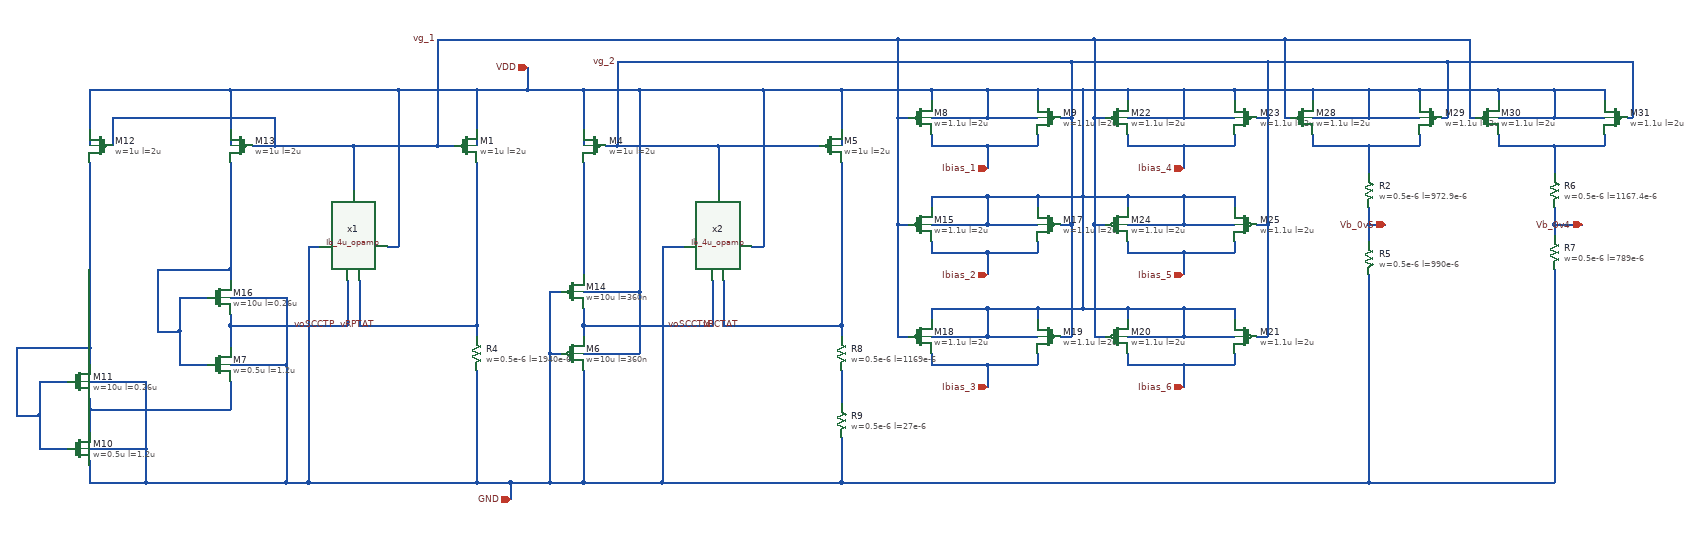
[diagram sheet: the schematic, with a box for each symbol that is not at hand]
v {xschem version=3.4.6 file_version=1.2}
G {}
K {}
V {}
S {}
E {}
N 1170 -670 1170 -650 {lab=voSCCTN}
N 1410 -990 1410 -910 {lab=vg_2}
N 1170 -1090 1170 -990 {lab=VDD}
N 1630 -1090 1630 -990 {lab=VDD}
N 290 -1090 540 -1090 {lab=VDD}
N 980 -1090 980 -990 {lab=VDD}
N 910 -990 940 -990 {lab=vg_1}
N 760 -990 910 -990 {lab=vg_1}
N 540 -1090 540 -990 {lab=VDD}
N 760 -990 760 -910 {lab=vg_1}
N 620 -990 760 -990 {lab=vg_1}
N 820 -810 840 -810 {lab=VDD}
N 840 -1090 840 -810 {lab=VDD}
N 540 -1090 840 -1090 {lab=VDD}
N 540 -670 540 -630 {lab=voSCCTP}
N 540 -720 640 -720 {lab=GND}
N 640 -720 640 -600 {lab=GND}
N 540 -600 640 -600 {lab=GND}
N 450 -720 500 -720 {lab=#net1}
N 450 -660 450 -600 {lab=#net1}
N 450 -600 500 -600 {lab=#net1}
N 540 -770 540 -750 {lab=#net1}
N 410 -660 450 -660 {lab=#net1}
N 450 -720 450 -660 {lab=#net1}
N 410 -770 410 -660 {lab=#net1}
N 410 -770 540 -770 {lab=#net1}
N 540 -960 540 -770 {lab=#net1}
N 540 -670 750 -670 {lab=voSCCTP}
N 540 -690 540 -670 {lab=voSCCTP}
N 750 -750 750 -670 {lab=voSCCTP}
N 290 -520 290 -480 {lab=#net2}
N 290 -570 390 -570 {lab=GND}
N 390 -570 390 -450 {lab=GND}
N 290 -450 390 -450 {lab=GND}
N 200 -570 250 -570 {lab=#net3}
N 200 -510 200 -450 {lab=#net3}
N 200 -450 250 -450 {lab=#net3}
N 160 -510 200 -510 {lab=#net3}
N 200 -570 200 -510 {lab=#net3}
N 290 -520 540 -520 {lab=#net2}
N 290 -540 290 -520 {lab=#net2}
N 540 -570 540 -520 {lab=#net2}
N 290 -630 290 -600 {lab=#net3}
N 290 -1090 290 -990 {lab=VDD}
N 330 -1040 330 -990 {lab=vg_1}
N 330 -1040 620 -1040 {lab=vg_1}
N 620 -1040 620 -990 {lab=vg_1}
N 580 -990 620 -990 {lab=vg_1}
N 290 -430 290 -390 {lab=GND}
N 160 -630 160 -510 {lab=#net3}
N 160 -630 290 -630 {lab=#net3}
N 290 -960 290 -630 {lab=#net3}
N 640 -600 640 -390 {lab=GND}
N 390 -390 640 -390 {lab=GND}
N 390 -450 390 -390 {lab=GND}
N 290 -390 390 -390 {lab=GND}
N 1170 -620 1270 -620 {lab=VDD}
N 1490 -1090 1630 -1090 {lab=VDD}
N 980 -670 980 -650 {lab=vRPTAT}
N 980 -590 980 -390 {lab=GND}
N 770 -750 770 -670 {lab=vRPTAT}
N 770 -670 980 -670 {lab=vRPTAT}
N 980 -960 980 -670 {lab=vRPTAT}
N 1630 -670 1630 -650 {lab=vRCTAT}
N 1420 -670 1630 -670 {lab=vRCTAT}
N 1630 -960 1630 -670 {lab=vRCTAT}
N 1420 -750 1420 -670 {lab=vRCTAT}
N 1400 -750 1400 -670 {lab=voSCCTN}
N 1170 -960 1170 -760 {lab=#net4}
N 1170 -590 1170 -390 {lab=GND}
N 1170 -670 1400 -670 {lab=voSCCTN}
N 1170 -700 1170 -670 {lab=voSCCTN}
N 1270 -730 1270 -620 {lab=VDD}
N 1170 -1090 1270 -1090 {lab=VDD}
N 1310 -810 1350 -810 {lab=GND}
N 1310 -810 1310 -390 {lab=GND}
N 1470 -810 1490 -810 {lab=VDD}
N 1490 -1090 1490 -810 {lab=VDD}
N 1270 -1090 1490 -1090 {lab=VDD}
N 680 -810 700 -810 {lab=GND}
N 680 -810 680 -390 {lab=GND}
N 1170 -730 1270 -730 {lab=VDD}
N 1270 -1090 1270 -730 {lab=VDD}
N 1410 -990 1590 -990 {lab=vg_2}
N 2570 -850 2600 -850 {lab=Vb_0v5}
N 2900 -850 2950 -850 {lab=Vb_0v4}
N 1630 -590 1630 -530 {lab=#net5}
N 1630 -470 1630 -390 {lab=GND}
N 640 -390 680 -390 {lab=GND}
N 1310 -390 1630 -390 {lab=GND}
N 1790 -1090 1790 -1070 {lab=VDD}
N 1890 -1090 1980 -1090 {lab=VDD}
N 1980 -1090 1980 -1070 {lab=VDD}
N 1890 -1040 1980 -1040 {lab=VDD}
N 1890 -1090 1890 -1040 {lab=VDD}
N 1790 -1090 1890 -1090 {lab=VDD}
N 1790 -1040 1890 -1040 {lab=VDD}
N 1790 -1010 1790 -990 {lab=Ibias_1}
N 1890 -990 1980 -990 {lab=Ibias_1}
N 1980 -1010 1980 -990 {lab=Ibias_1}
N 1790 -900 1790 -880 {lab=VDD}
N 1890 -900 1980 -900 {lab=VDD}
N 1980 -900 1980 -880 {lab=VDD}
N 1890 -850 1980 -850 {lab=VDD}
N 1890 -900 1890 -850 {lab=VDD}
N 1790 -900 1890 -900 {lab=VDD}
N 1790 -850 1890 -850 {lab=VDD}
N 1790 -820 1790 -800 {lab=Ibias_2}
N 1890 -800 1980 -800 {lab=Ibias_2}
N 1980 -820 1980 -800 {lab=Ibias_2}
N 1790 -700 1790 -680 {lab=VDD}
N 1890 -700 1980 -700 {lab=VDD}
N 1980 -700 1980 -680 {lab=VDD}
N 1890 -650 1980 -650 {lab=VDD}
N 1890 -700 1890 -650 {lab=VDD}
N 1790 -700 1890 -700 {lab=VDD}
N 1790 -650 1890 -650 {lab=VDD}
N 1790 -620 1790 -600 {lab=Ibias_3}
N 1890 -600 1980 -600 {lab=Ibias_3}
N 1980 -620 1980 -600 {lab=Ibias_3}
N 2140 -700 2140 -680 {lab=VDD}
N 2240 -700 2330 -700 {lab=VDD}
N 2330 -700 2330 -680 {lab=VDD}
N 2240 -650 2330 -650 {lab=VDD}
N 2240 -700 2240 -650 {lab=VDD}
N 2140 -700 2240 -700 {lab=VDD}
N 2140 -650 2240 -650 {lab=VDD}
N 2140 -620 2140 -600 {lab=Ibias_6}
N 2240 -600 2330 -600 {lab=Ibias_6}
N 2330 -620 2330 -600 {lab=Ibias_6}
N 2140 -1090 2140 -1070 {lab=VDD}
N 2240 -1090 2330 -1090 {lab=VDD}
N 2330 -1090 2330 -1070 {lab=VDD}
N 2240 -1040 2330 -1040 {lab=VDD}
N 2240 -1090 2240 -1040 {lab=VDD}
N 2140 -1090 2240 -1090 {lab=VDD}
N 2140 -1040 2240 -1040 {lab=VDD}
N 2140 -1010 2140 -990 {lab=Ibias_4}
N 2240 -990 2330 -990 {lab=Ibias_4}
N 2330 -1010 2330 -990 {lab=Ibias_4}
N 2140 -900 2140 -880 {lab=VDD}
N 2330 -900 2330 -880 {lab=VDD}
N 2240 -850 2330 -850 {lab=VDD}
N 2240 -900 2240 -850 {lab=VDD}
N 2140 -850 2240 -850 {lab=VDD}
N 2140 -820 2140 -800 {lab=Ibias_5}
N 2240 -800 2330 -800 {lab=Ibias_5}
N 2330 -820 2330 -800 {lab=Ibias_5}
N 2240 -900 2330 -900 {lab=VDD}
N 1890 -990 1890 -950 {lab=Ibias_1}
N 1790 -990 1890 -990 {lab=Ibias_1}
N 1890 -800 1890 -760 {lab=Ibias_2}
N 1790 -800 1890 -800 {lab=Ibias_2}
N 1890 -600 1890 -560 {lab=Ibias_3}
N 1790 -600 1890 -600 {lab=Ibias_3}
N 2240 -600 2240 -560 {lab=Ibias_6}
N 2140 -600 2240 -600 {lab=Ibias_6}
N 2240 -990 2240 -950 {lab=Ibias_4}
N 2140 -990 2240 -990 {lab=Ibias_4}
N 2240 -800 2240 -760 {lab=Ibias_5}
N 2140 -800 2240 -800 {lab=Ibias_5}
N 2140 -900 2240 -900 {lab=VDD}
N 2470 -1090 2470 -1070 {lab=VDD}
N 2570 -1090 2660 -1090 {lab=VDD}
N 2660 -1090 2660 -1070 {lab=VDD}
N 2570 -1040 2660 -1040 {lab=VDD}
N 2570 -1090 2570 -1040 {lab=VDD}
N 2470 -1090 2570 -1090 {lab=VDD}
N 2470 -1040 2570 -1040 {lab=VDD}
N 2470 -1010 2470 -990 {lab=#net6}
N 2660 -1010 2660 -990 {lab=#net6}
N 2330 -1090 2470 -1090 {lab=VDD}
N 2800 -1090 2800 -1070 {lab=VDD}
N 2900 -1090 2990 -1090 {lab=VDD}
N 2990 -1090 2990 -1070 {lab=VDD}
N 2900 -1040 2990 -1040 {lab=VDD}
N 2900 -1090 2900 -1040 {lab=VDD}
N 2800 -1090 2900 -1090 {lab=VDD}
N 2800 -1040 2900 -1040 {lab=VDD}
N 2800 -1010 2800 -990 {lab=#net7}
N 2990 -1010 2990 -990 {lab=#net7}
N 2660 -1090 2800 -1090 {lab=VDD}
N 1730 -850 1730 -650 {lab=vg_1}
N 2420 -1180 2420 -1040 {lab=vg_1}
N 2750 -1180 2750 -1040 {lab=vg_1}
N 3040 -1140 3040 -1040 {lab=vg_2}
N 2710 -1140 3040 -1140 {lab=vg_2}
N 2710 -1140 2710 -1040 {lab=vg_2}
N 910 -1180 910 -990 {lab=vg_1}
N 1070 -1130 1070 -1090 {lab=VDD}
N 1070 -1090 1170 -1090 {lab=VDD}
N 1230 -1140 1230 -990 {lab=vg_2}
N 1040 -390 1040 -360 {lab=GND}
N 980 -390 1040 -390 {lab=GND}
N 1630 -1090 1790 -1090 {lab=VDD}
N 2040 -1140 2390 -1140 {lab=vg_2}
N 980 -1090 1070 -1090 {lab=VDD}
N 1110 -390 1170 -390 {lab=GND}
N 1110 -730 1130 -730 {lab=GND}
N 1110 -730 1110 -620 {lab=GND}
N 1110 -620 1130 -620 {lab=GND}
N 1110 -620 1110 -390 {lab=GND}
N 1040 -390 1110 -390 {lab=GND}
N 2060 -900 2140 -900 {lab=VDD}
N 2060 -1090 2140 -1090 {lab=VDD}
N 2060 -700 2140 -700 {lab=VDD}
N 2390 -1140 2710 -1140 {lab=vg_2}
N 2060 -1090 2060 -900 {lab=VDD}
N 1980 -1090 2060 -1090 {lab=VDD}
N 1980 -900 2060 -900 {lab=VDD}
N 2060 -900 2060 -700 {lab=VDD}
N 1980 -700 2060 -700 {lab=VDD}
N 2390 -850 2390 -650 {lab=vg_2}
N 2370 -650 2390 -650 {lab=vg_2}
N 2370 -850 2390 -850 {lab=vg_2}
N 2390 -1040 2390 -850 {lab=vg_2}
N 2370 -1040 2390 -1040 {lab=vg_2}
N 2390 -1140 2390 -1040 {lab=vg_2}
N 2080 -850 2080 -650 {lab=vg_1}
N 2080 -650 2100 -650 {lab=vg_1}
N 2080 -850 2100 -850 {lab=vg_1}
N 2080 -1040 2080 -850 {lab=vg_1}
N 2080 -1040 2100 -1040 {lab=vg_1}
N 2080 -1180 2080 -1040 {lab=vg_1}
N 2040 -850 2040 -650 {lab=vg_2}
N 2020 -650 2040 -650 {lab=vg_2}
N 2020 -850 2040 -850 {lab=vg_2}
N 2040 -1040 2040 -850 {lab=vg_2}
N 2020 -1040 2040 -1040 {lab=vg_2}
N 2040 -1140 2040 -1040 {lab=vg_2}
N 1730 -1180 2080 -1180 {lab=vg_1}
N 1730 -1040 1750 -1040 {lab=vg_1}
N 1730 -1180 1730 -1040 {lab=vg_1}
N 1730 -850 1750 -850 {lab=vg_1}
N 1730 -1040 1730 -850 {lab=vg_1}
N 1730 -650 1750 -650 {lab=vg_1}
N 2080 -1180 2420 -1180 {lab=vg_1}
N 2420 -1040 2430 -1040 {lab=vg_1}
N 2700 -1040 2710 -1040 {lab=vg_2}
N 2420 -1180 2750 -1180 {lab=vg_1}
N 2750 -1040 2760 -1040 {lab=vg_1}
N 3030 -1040 3040 -1040 {lab=vg_2}
N 1210 -990 1230 -990 {lab=vg_2}
N 910 -1180 1730 -1180 {lab=vg_1}
N 1230 -1140 2040 -1140 {lab=vg_2}
N 2570 -390 2900 -390 {lab=GND}
N 2570 -990 2660 -990 {lab=#net6}
N 2900 -990 2990 -990 {lab=#net7}
N 2570 -990 2570 -940 {lab=#net6}
N 2470 -990 2570 -990 {lab=#net6}
N 2570 -880 2570 -850 {lab=Vb_0v5}
N 2570 -850 2570 -820 {lab=Vb_0v5}
N 2570 -760 2570 -390 {lab=GND}
N 1630 -390 2570 -390 {lab=GND}
N 2900 -990 2900 -940 {lab=#net7}
N 2800 -990 2900 -990 {lab=#net7}
N 2900 -850 2900 -830 {lab=Vb_0v4}
N 2900 -880 2900 -850 {lab=Vb_0v4}
N 2900 -770 2900 -390 {lab=GND}
N 1230 -990 1410 -990 {lab=vg_2}
N 1170 -390 1310 -390 {lab=GND}
N 840 -1090 980 -1090 {lab=VDD}
N 680 -390 980 -390 {lab=GND}
C {iopin.sym} 1070 -1130 0 0 {name=p1 lab=VDD}
C {iopin.sym} 1040 -360 0 0 {name=p2 lab=GND}
C {iopin.sym} 1890 -950 0 0 {name=p3 lab=Ibias_1}
C {lab_pin.sym} 730 -670 3 0 {name=p9 sig_type=std_logic lab=voSCCTP}
C {lab_pin.sym} 1400 -670 3 0 {name=p10 sig_type=std_logic lab=voSCCTN}
C {lab_pin.sym} 1450 -670 3 0 {name=p11 sig_type=std_logic lab=vRCTAT}
C {lab_pin.sym} 800 -670 3 0 {name=p12 sig_type=std_logic lab=vRPTAT}
C {sg13g2_pr/sg13_lv_pmos.sym} 960 -990 0 0 {name=M1
l=2u
w=1u
ng=1
m=1
model=sg13_lv_pmos
spiceprefix=X
}
C {sg13g2_pr/sg13_lv_pmos.sym} 1190 -990 0 1 {name=M4
l=2u
w=1u
ng=1
m=1
model=sg13_lv_pmos
spiceprefix=X
}
C {sg13g2_pr/sg13_lv_pmos.sym} 310 -990 0 1 {name=M12
l=2u
w=1u
ng=1
m=1
model=sg13_lv_pmos
spiceprefix=X
}
C {sg13g2_pr/sg13_lv_pmos.sym} 560 -990 0 1 {name=M13
l=2u
w=1u
ng=1
m=1
model=sg13_lv_pmos
spiceprefix=X
}
C {sg13g2_pr/sg13_lv_pmos.sym} 1610 -990 0 0 {name=M5
l=2u
w=1u
ng=1
m=1
model=sg13_lv_pmos
spiceprefix=X
}
C {sg13g2_pr/sg13_lv_nmos.sym} 520 -600 0 0 {name=M7
l=1.2u
w=0.5u
ng=1
m=1
model=sg13_lv_nmos
spiceprefix=X
}
C {sg13g2_pr/sg13_lv_nmos.sym} 270 -450 0 0 {name=M10
l=1.2u
w=0.5u
ng=1
m=1
model=sg13_lv_nmos
spiceprefix=X
}
C {sg13g2_pr/sg13_lv_nmos.sym} 270 -570 0 0 {name=M11
l=0.26u
w=10u
ng=1
m=30
model=sg13_lv_nmos
spiceprefix=X
}
C {sg13g2_pr/sg13_lv_nmos.sym} 520 -720 0 0 {name=M16
l=0.26u
w=10u
ng=1
m=30
model=sg13_lv_nmos
spiceprefix=X
}
C {sg13g2_pr/sg13_lv_pmos.sym} 1150 -620 0 0 {name=M6
l=360n
w=10u
ng=1
m=20
model=sg13_lv_pmos
spiceprefix=X
}
C {sg13g2_pr/sg13_lv_pmos.sym} 1150 -730 0 0 {name=M14
l=360n
w=10u
ng=1
m=1
model=sg13_lv_pmos
spiceprefix=X
}
C {iopin.sym} 1890 -760 0 0 {name=p4 lab=Ibias_2}
C {iopin.sym} 1890 -560 0 0 {name=p5 lab=Ibias_3}
C {iopin.sym} 2240 -950 0 0 {name=p6 lab=Ibias_4}
C {iopin.sym} 2240 -760 0 0 {name=p7 lab=Ibias_5}
C {iopin.sym} 2240 -560 0 0 {name=p8 lab=Ibias_6}
C {lab_pin.sym} 910 -1180 0 0 {name=p14 sig_type=std_logic lab=vg_1}
C {/shared/designs/SSDOR_w_startup_1V_ihp/Ib_4u/Ib_4u_opamp/Ib_4u_opamp.sym} 700 -750 1 1 {name=x1}
C {/shared/designs/SSDOR_w_startup_1V_ihp/Ib_4u/Ib_4u_opamp/Ib_4u_opamp.sym} 1350 -750 1 1 {name=x2}
C {iopin.sym} 2950 -850 0 0 {name=p16 lab=Vb_0v4}
C {iopin.sym} 2600 -850 0 0 {name=p17 lab=Vb_0v5}
C {sg13g2_pr/sg13_lv_pmos.sym} 1770 -1040 0 0 {name=M8
l=2u
w=1.1u
ng=1
m=6
model=sg13_lv_pmos
spiceprefix=X
}
C {sg13g2_pr/sg13_lv_pmos.sym} 2000 -1040 0 1 {name=M9
l=2u
w=1.1u
ng=1
m=6
model=sg13_lv_pmos
spiceprefix=X
}
C {lab_pin.sym} 1230 -1140 0 0 {name=p19 sig_type=std_logic lab=vg_2}
C {sg13g2_pr/sg13_lv_pmos.sym} 1770 -850 0 0 {name=M15
l=2u
w=1.1u
ng=1
m=6
model=sg13_lv_pmos
spiceprefix=X
}
C {sg13g2_pr/sg13_lv_pmos.sym} 2000 -850 0 1 {name=M17
l=2u
w=1.1u
ng=1
m=6
model=sg13_lv_pmos
spiceprefix=X
}
C {sg13g2_pr/sg13_lv_pmos.sym} 1770 -650 0 0 {name=M18
l=2u
w=1.1u
ng=1
m=6
model=sg13_lv_pmos
spiceprefix=X
}
C {sg13g2_pr/sg13_lv_pmos.sym} 2000 -650 0 1 {name=M19
l=2u
w=1.1u
ng=1
m=6
model=sg13_lv_pmos
spiceprefix=X
}
C {sg13g2_pr/sg13_lv_pmos.sym} 2120 -650 0 0 {name=M20
l=2u
w=1.1u
ng=1
m=6
model=sg13_lv_pmos
spiceprefix=X
}
C {sg13g2_pr/sg13_lv_pmos.sym} 2350 -650 0 1 {name=M21
l=2u
w=1.1u
ng=1
m=6
model=sg13_lv_pmos
spiceprefix=X
}
C {sg13g2_pr/sg13_lv_pmos.sym} 2120 -1040 0 0 {name=M22
l=2u
w=1.1u
ng=1
m=6
model=sg13_lv_pmos
spiceprefix=X
}
C {sg13g2_pr/sg13_lv_pmos.sym} 2350 -1040 0 1 {name=M23
l=2u
w=1.1u
ng=1
m=6
model=sg13_lv_pmos
spiceprefix=X
}
C {sg13g2_pr/sg13_lv_pmos.sym} 2120 -850 0 0 {name=M24
l=2u
w=1.1u
ng=1
m=6
model=sg13_lv_pmos
spiceprefix=X
}
C {sg13g2_pr/sg13_lv_pmos.sym} 2350 -850 0 1 {name=M25
l=2u
w=1.1u
ng=1
m=6
model=sg13_lv_pmos
spiceprefix=X
}
C {sg13g2_pr/sg13_lv_pmos.sym} 2450 -1040 0 0 {name=M28
l=2u
w=1.1u
ng=1
m=6
model=sg13_lv_pmos
spiceprefix=X
}
C {sg13g2_pr/sg13_lv_pmos.sym} 2680 -1040 0 1 {name=M29
l=2u
w=1.1u
ng=1
m=6
model=sg13_lv_pmos
spiceprefix=X
}
C {sg13g2_pr/sg13_lv_pmos.sym} 2780 -1040 0 0 {name=M30
l=2u
w=1.1u
ng=1
m=6
model=sg13_lv_pmos
spiceprefix=X
}
C {sg13g2_pr/sg13_lv_pmos.sym} 3010 -1040 0 1 {name=M31
l=2u
w=1.1u
ng=1
m=6
model=sg13_lv_pmos
spiceprefix=X
}
C {sg13g2_pr/rppd.sym} 980 -620 0 0 {name=R4
w=0.5e-6
l=1940e-6
model=rppd
body=GND
spiceprefix=X
b=0
m=1
}
C {sg13g2_pr/rppd.sym} 1630 -620 0 0 {name=R8
w=0.5e-6
l=1169e-6
model=rppd
body=GND
spiceprefix=X
b=0
m=1
}
C {sg13g2_pr/rhigh.sym} 1630 -500 0 0 {name=R9
w=0.5e-6
l=27e-6
model=rhigh
body=GND
spiceprefix=X
b=0
m=1
}
C {sg13g2_pr/rppd.sym} 2570 -910 0 0 {name=R2
w=0.5e-6
l=972.9e-6
model=rppd
body=GND
spiceprefix=X
b=0
m=1
}
C {sg13g2_pr/rppd.sym} 2570 -790 0 0 {name=R5
w=0.5e-6
l=990e-6
model=rppd
body=GND
spiceprefix=X
b=0
m=1
}
C {sg13g2_pr/rppd.sym} 2900 -910 0 0 {name=R6
w=0.5e-6
l=1167.4e-6
model=rppd
body=GND
spiceprefix=X
b=0
m=1
}
C {sg13g2_pr/rppd.sym} 2900 -800 0 0 {name=R7
w=0.5e-6
l=789e-6
model=rppd
body=GND
spiceprefix=X
b=0
m=1
}
